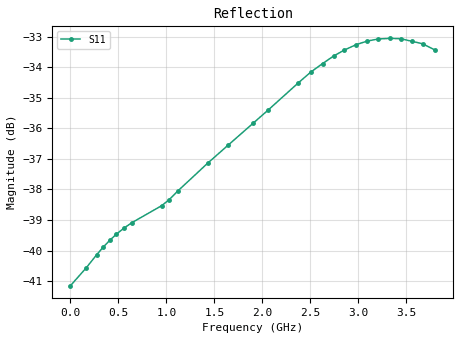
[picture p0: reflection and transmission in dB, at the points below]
! ListType=Lin
!!SAA-2 female load 0.1 to 3800MHz 500 points
# MHz S RI R 50
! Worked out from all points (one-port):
!   500 points, 100 kHz to 3.8 GHz, reference 50 ohm
!   lowest |S11| = -41.1 dB at 100 kHz (marker M1), VSWR 1.02, Z = 50.9 - j0.00585 ohm
!   |S11| at or under -10 dB: start of sweep to end of sweep
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0.1  0.00876 -5.75e-05
160.0156  0.00932 -0.000748
274.2411  0.00959 -0.00223
342.7764  0.00964 -0.00313
411.3116  0.00959 -0.00401
479.8469  0.00946 -0.00487
555.9972  0.0092 -0.0058
639.7625  0.00878 -0.0068
951.9788  0.00602 -0.0102
1028.129  0.00506 -0.011
1119.509  0.00388 -0.0119
1431.726  -0.000334 -0.0139
1644.946  -0.00334 -0.0145
1903.858  -0.00712 -0.0145
2056.158  -0.00941 -0.0141
2375.989  -0.0136 -0.013
2505.445  -0.015 -0.0126
2627.285  -0.0162 -0.0121
2741.511  -0.0172 -0.0117
2855.736  -0.0181 -0.0112
2977.577  -0.0189 -0.0107
3091.802  -0.0195 -0.0102
3206.028  -0.02 -0.0096
3327.868  -0.0204 -0.00885
3442.094  -0.0207 -0.00805
3556.319  -0.0208 -0.00715
3670.544  -0.0209 -0.00616
3800  -0.0207 -0.00493
